# Copyright lowRISC contributors (OpenTitan project).
# Licensed under the Apache License, Version 2.0, see LICENSE for details.
# SPDX-License-Identifier: Apache-2.0
#
# This file was derived by lowRISC contributors (OpenTitan project) from the
# IHP Open PDK SRAM abstract RM_IHPSG13_1P_8192x32_c4.lef
# (https://github.com/IHP-GmbH/IHP-Open-PDK, ihp-sg13g2/libs.ref/sg13g2_sram/lef).
# It is a synthetic abstract, not an IHP release: the macro size and pins come
# from the Liberty view, the pin shapes, power straps and antenna values from
# the IHP abstract. IHP's original notice follows:
#
#   Copyright 2023 IHP PDK Authors
#
#   Licensed under the Apache License, Version 2.0 (the "License");
#   you may not use this file except in compliance with the License.
#   You may obtain a copy of the License at
#
#      https://www.apache.org/licenses/LICENSE-2.0
#
#   Unless required by applicable law or agreed to in writing, software
#   distributed under the License is distributed on an "AS IS" BASIS,
#   WITHOUT WARRANTIES OR CONDITIONS OF ANY KIND, either express or implied.
#   See the License for the specific language governing permissions and
#   limitations under the License.
#
#   Generated on Mon Apr  7 14:15:46 2025
#
# Generated by gen_synthetic_lef.py from the Liberty view. Do not edit.
# Synthetic abstract: no physical layout exists behind this macro.

VERSION 5.7 ;
BUSBITCHARS "[]" ;
DIVIDERCHAR "/" ;

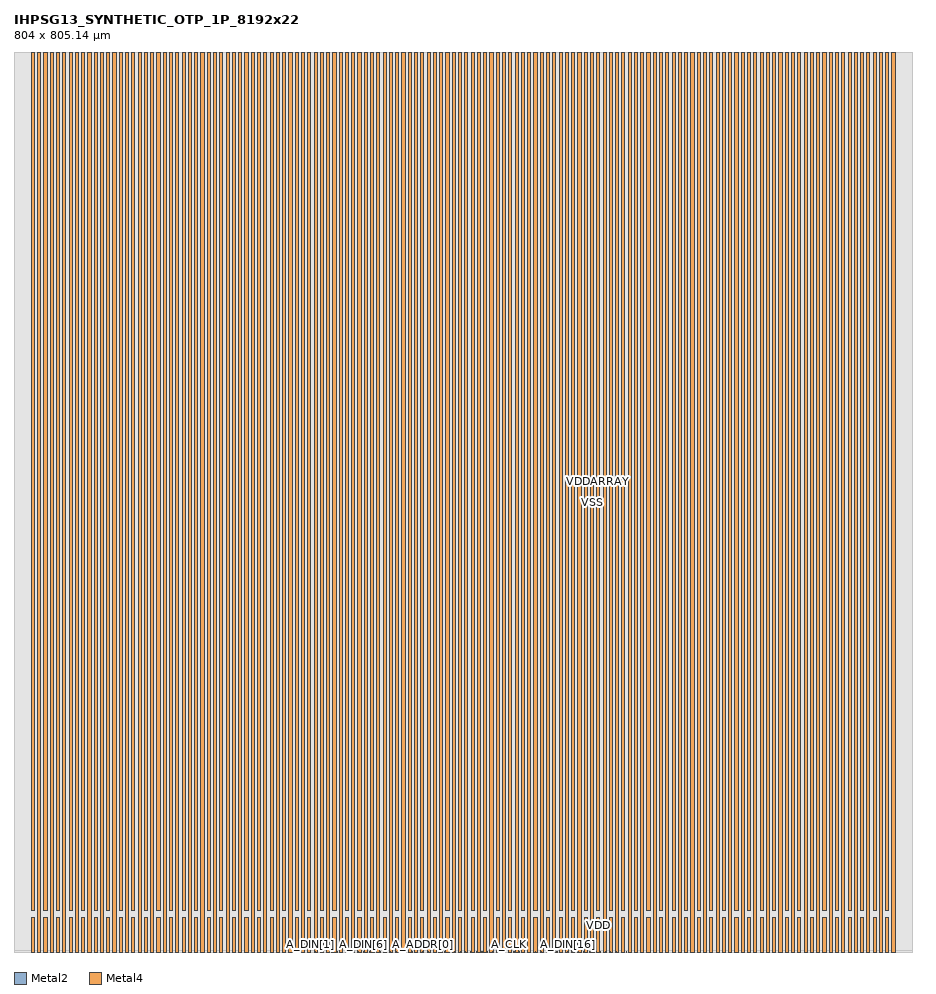
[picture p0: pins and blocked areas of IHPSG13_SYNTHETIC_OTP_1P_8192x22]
MACRO IHPSG13_SYNTHETIC_OTP_1P_8192x22
  CLASS BLOCK ;
  ORIGIN 0 0 ;
  FOREIGN IHPSG13_SYNTHETIC_OTP_1P_8192x22 0 0 ;
  SIZE 804 BY 805.14 ;
  SYMMETRY X Y R90 ;
  PIN A_DIN[0]
    DIRECTION INPUT ;
    USE SIGNAL ;
    ANTENNAMODEL OXIDE1 ;
      ANTENNAGATEAREA 0.20085 LAYER Metal2 ;
    PORT
      LAYER Metal2 ;
        RECT 255.23 0 255.49 0.26 ;
    END
  END A_DIN[0]
  PIN A_DOUT[0]
    DIRECTION OUTPUT ;
    USE SIGNAL ;
    ANTENNADIFFAREA 0.988 LAYER Metal2 ;
    PORT
      LAYER Metal2 ;
        RECT 260.03 0 260.29 0.26 ;
    END
  END A_DOUT[0]
  PIN A_DIN[1]
    DIRECTION INPUT ;
    USE SIGNAL ;
    ANTENNAMODEL OXIDE1 ;
      ANTENNAGATEAREA 0.20085 LAYER Metal2 ;
    PORT
      LAYER Metal2 ;
        RECT 264.83 0 265.09 0.26 ;
    END
  END A_DIN[1]
  PIN A_DOUT[1]
    DIRECTION OUTPUT ;
    USE SIGNAL ;
    ANTENNADIFFAREA 0.988 LAYER Metal2 ;
    PORT
      LAYER Metal2 ;
        RECT 269.63 0 269.89 0.26 ;
    END
  END A_DOUT[1]
  PIN A_DIN[2]
    DIRECTION INPUT ;
    USE SIGNAL ;
    ANTENNAMODEL OXIDE1 ;
      ANTENNAGATEAREA 0.20085 LAYER Metal2 ;
    PORT
      LAYER Metal2 ;
        RECT 274.43 0 274.69 0.26 ;
    END
  END A_DIN[2]
  PIN A_DOUT[2]
    DIRECTION OUTPUT ;
    USE SIGNAL ;
    ANTENNADIFFAREA 0.988 LAYER Metal2 ;
    PORT
      LAYER Metal2 ;
        RECT 279.23 0 279.49 0.26 ;
    END
  END A_DOUT[2]
  PIN A_DIN[3]
    DIRECTION INPUT ;
    USE SIGNAL ;
    ANTENNAMODEL OXIDE1 ;
      ANTENNAGATEAREA 0.20085 LAYER Metal2 ;
    PORT
      LAYER Metal2 ;
        RECT 284.03 0 284.29 0.26 ;
    END
  END A_DIN[3]
  PIN A_DOUT[3]
    DIRECTION OUTPUT ;
    USE SIGNAL ;
    ANTENNADIFFAREA 0.988 LAYER Metal2 ;
    PORT
      LAYER Metal2 ;
        RECT 288.83 0 289.09 0.26 ;
    END
  END A_DOUT[3]
  PIN A_DIN[4]
    DIRECTION INPUT ;
    USE SIGNAL ;
    ANTENNAMODEL OXIDE1 ;
      ANTENNAGATEAREA 0.20085 LAYER Metal2 ;
    PORT
      LAYER Metal2 ;
        RECT 293.63 0 293.89 0.26 ;
    END
  END A_DIN[4]
  PIN A_DOUT[4]
    DIRECTION OUTPUT ;
    USE SIGNAL ;
    ANTENNADIFFAREA 0.988 LAYER Metal2 ;
    PORT
      LAYER Metal2 ;
        RECT 298.43 0 298.69 0.26 ;
    END
  END A_DOUT[4]
  PIN A_DIN[5]
    DIRECTION INPUT ;
    USE SIGNAL ;
    ANTENNAMODEL OXIDE1 ;
      ANTENNAGATEAREA 0.20085 LAYER Metal2 ;
    PORT
      LAYER Metal2 ;
        RECT 303.23 0 303.49 0.26 ;
    END
  END A_DIN[5]
  PIN A_DOUT[5]
    DIRECTION OUTPUT ;
    USE SIGNAL ;
    ANTENNADIFFAREA 0.988 LAYER Metal2 ;
    PORT
      LAYER Metal2 ;
        RECT 308.03 0 308.29 0.26 ;
    END
  END A_DOUT[5]
  PIN A_DIN[6]
    DIRECTION INPUT ;
    USE SIGNAL ;
    ANTENNAMODEL OXIDE1 ;
      ANTENNAGATEAREA 0.20085 LAYER Metal2 ;
    PORT
      LAYER Metal2 ;
        RECT 312.83 0 313.09 0.26 ;
    END
  END A_DIN[6]
  PIN A_DOUT[6]
    DIRECTION OUTPUT ;
    USE SIGNAL ;
    ANTENNADIFFAREA 0.988 LAYER Metal2 ;
    PORT
      LAYER Metal2 ;
        RECT 317.63 0 317.89 0.26 ;
    END
  END A_DOUT[6]
  PIN A_DIN[7]
    DIRECTION INPUT ;
    USE SIGNAL ;
    ANTENNAMODEL OXIDE1 ;
      ANTENNAGATEAREA 0.20085 LAYER Metal2 ;
    PORT
      LAYER Metal2 ;
        RECT 322.43 0 322.69 0.26 ;
    END
  END A_DIN[7]
  PIN A_DOUT[7]
    DIRECTION OUTPUT ;
    USE SIGNAL ;
    ANTENNADIFFAREA 0.988 LAYER Metal2 ;
    PORT
      LAYER Metal2 ;
        RECT 327.23 0 327.49 0.26 ;
    END
  END A_DOUT[7]
  PIN A_DIN[8]
    DIRECTION INPUT ;
    USE SIGNAL ;
    ANTENNAMODEL OXIDE1 ;
      ANTENNAGATEAREA 0.20085 LAYER Metal2 ;
    PORT
      LAYER Metal2 ;
        RECT 332.03 0 332.29 0.26 ;
    END
  END A_DIN[8]
  PIN A_DOUT[8]
    DIRECTION OUTPUT ;
    USE SIGNAL ;
    ANTENNADIFFAREA 0.988 LAYER Metal2 ;
    PORT
      LAYER Metal2 ;
        RECT 336.83 0 337.09 0.26 ;
    END
  END A_DOUT[8]
  PIN A_DIN[9]
    DIRECTION INPUT ;
    USE SIGNAL ;
    ANTENNAMODEL OXIDE1 ;
      ANTENNAGATEAREA 0.20085 LAYER Metal2 ;
    PORT
      LAYER Metal2 ;
        RECT 341.63 0 341.89 0.26 ;
    END
  END A_DIN[9]
  PIN A_DOUT[9]
    DIRECTION OUTPUT ;
    USE SIGNAL ;
    ANTENNADIFFAREA 0.988 LAYER Metal2 ;
    PORT
      LAYER Metal2 ;
        RECT 346.43 0 346.69 0.26 ;
    END
  END A_DOUT[9]
  PIN A_DIN[10]
    DIRECTION INPUT ;
    USE SIGNAL ;
    ANTENNAMODEL OXIDE1 ;
      ANTENNAGATEAREA 0.20085 LAYER Metal2 ;
    PORT
      LAYER Metal2 ;
        RECT 351.23 0 351.49 0.26 ;
    END
  END A_DIN[10]
  PIN A_DOUT[10]
    DIRECTION OUTPUT ;
    USE SIGNAL ;
    ANTENNADIFFAREA 0.988 LAYER Metal2 ;
    PORT
      LAYER Metal2 ;
        RECT 356.03 0 356.29 0.26 ;
    END
  END A_DOUT[10]
  PIN A_DLY
    DIRECTION INPUT ;
    USE SIGNAL ;
    ANTENNAMODEL OXIDE1 ;
      ANTENNAGATEAREA 0.20085 LAYER Metal2 ;
    PORT
      LAYER Metal2 ;
        RECT 360.83 0 361.09 0.26 ;
    END
  END A_DLY
  PIN A_ADDR[0]
    DIRECTION INPUT ;
    USE SIGNAL ;
    ANTENNAMODEL OXIDE1 ;
      ANTENNAGATEAREA 0.20085 LAYER Metal2 ;
    PORT
      LAYER Metal2 ;
        RECT 365.63 0 365.89 0.26 ;
    END
  END A_ADDR[0]
  PIN A_ADDR[1]
    DIRECTION INPUT ;
    USE SIGNAL ;
    ANTENNAMODEL OXIDE1 ;
      ANTENNAGATEAREA 0.20085 LAYER Metal2 ;
    PORT
      LAYER Metal2 ;
        RECT 370.43 0 370.69 0.26 ;
    END
  END A_ADDR[1]
  PIN A_ADDR[2]
    DIRECTION INPUT ;
    USE SIGNAL ;
    ANTENNAMODEL OXIDE1 ;
      ANTENNAGATEAREA 0.20085 LAYER Metal2 ;
    PORT
      LAYER Metal2 ;
        RECT 375.23 0 375.49 0.26 ;
    END
  END A_ADDR[2]
  PIN A_ADDR[3]
    DIRECTION INPUT ;
    USE SIGNAL ;
    ANTENNAMODEL OXIDE1 ;
      ANTENNAGATEAREA 0.20085 LAYER Metal2 ;
    PORT
      LAYER Metal2 ;
        RECT 380.03 0 380.29 0.26 ;
    END
  END A_ADDR[3]
  PIN A_ADDR[4]
    DIRECTION INPUT ;
    USE SIGNAL ;
    ANTENNAMODEL OXIDE1 ;
      ANTENNAGATEAREA 0.20085 LAYER Metal2 ;
    PORT
      LAYER Metal2 ;
        RECT 384.83 0 385.09 0.26 ;
    END
  END A_ADDR[4]
  PIN A_ADDR[5]
    DIRECTION INPUT ;
    USE SIGNAL ;
    ANTENNAMODEL OXIDE1 ;
      ANTENNAGATEAREA 0.20085 LAYER Metal2 ;
    PORT
      LAYER Metal2 ;
        RECT 389.63 0 389.89 0.26 ;
    END
  END A_ADDR[5]
  PIN A_ADDR[6]
    DIRECTION INPUT ;
    USE SIGNAL ;
    ANTENNAMODEL OXIDE1 ;
      ANTENNAGATEAREA 0.20085 LAYER Metal2 ;
    PORT
      LAYER Metal2 ;
        RECT 394.43 0 394.69 0.26 ;
    END
  END A_ADDR[6]
  PIN A_ADDR[7]
    DIRECTION INPUT ;
    USE SIGNAL ;
    ANTENNAMODEL OXIDE1 ;
      ANTENNAGATEAREA 0.20085 LAYER Metal2 ;
    PORT
      LAYER Metal2 ;
        RECT 399.23 0 399.49 0.26 ;
    END
  END A_ADDR[7]
  PIN A_ADDR[8]
    DIRECTION INPUT ;
    USE SIGNAL ;
    ANTENNAMODEL OXIDE1 ;
      ANTENNAGATEAREA 0.20085 LAYER Metal2 ;
    PORT
      LAYER Metal2 ;
        RECT 404.03 0 404.29 0.26 ;
    END
  END A_ADDR[8]
  PIN A_ADDR[9]
    DIRECTION INPUT ;
    USE SIGNAL ;
    ANTENNAMODEL OXIDE1 ;
      ANTENNAGATEAREA 0.20085 LAYER Metal2 ;
    PORT
      LAYER Metal2 ;
        RECT 408.83 0 409.09 0.26 ;
    END
  END A_ADDR[9]
  PIN A_ADDR[10]
    DIRECTION INPUT ;
    USE SIGNAL ;
    ANTENNAMODEL OXIDE1 ;
      ANTENNAGATEAREA 0.20085 LAYER Metal2 ;
    PORT
      LAYER Metal2 ;
        RECT 413.63 0 413.89 0.26 ;
    END
  END A_ADDR[10]
  PIN A_ADDR[11]
    DIRECTION INPUT ;
    USE SIGNAL ;
    ANTENNAMODEL OXIDE1 ;
      ANTENNAGATEAREA 0.20085 LAYER Metal2 ;
    PORT
      LAYER Metal2 ;
        RECT 418.43 0 418.69 0.26 ;
    END
  END A_ADDR[11]
  PIN A_ADDR[12]
    DIRECTION INPUT ;
    USE SIGNAL ;
    ANTENNAMODEL OXIDE1 ;
      ANTENNAGATEAREA 0.20085 LAYER Metal2 ;
    PORT
      LAYER Metal2 ;
        RECT 423.23 0 423.49 0.26 ;
    END
  END A_ADDR[12]
  PIN A_WEN
    DIRECTION INPUT ;
    USE SIGNAL ;
    ANTENNAMODEL OXIDE1 ;
      ANTENNAGATEAREA 0.20085 LAYER Metal2 ;
    PORT
      LAYER Metal2 ;
        RECT 428.03 0 428.29 0.26 ;
    END
  END A_WEN
  PIN A_REN
    DIRECTION INPUT ;
    USE SIGNAL ;
    ANTENNAMODEL OXIDE1 ;
      ANTENNAGATEAREA 0.20085 LAYER Metal2 ;
    PORT
      LAYER Metal2 ;
        RECT 432.83 0 433.09 0.26 ;
    END
  END A_REN
  PIN A_MEN
    DIRECTION INPUT ;
    USE SIGNAL ;
    ANTENNAMODEL OXIDE1 ;
      ANTENNAGATEAREA 0.20085 LAYER Metal2 ;
    PORT
      LAYER Metal2 ;
        RECT 437.63 0 437.89 0.26 ;
    END
  END A_MEN
  PIN A_CLK
    DIRECTION INPUT ;
    USE SIGNAL ;
    ANTENNAMODEL OXIDE1 ;
      ANTENNAGATEAREA 0.20085 LAYER Metal2 ;
    PORT
      LAYER Metal2 ;
        RECT 442.43 0 442.69 0.26 ;
    END
  END A_CLK
  PIN A_DIN[11]
    DIRECTION INPUT ;
    USE SIGNAL ;
    ANTENNAMODEL OXIDE1 ;
      ANTENNAGATEAREA 0.20085 LAYER Metal2 ;
    PORT
      LAYER Metal2 ;
        RECT 447.23 0 447.49 0.26 ;
    END
  END A_DIN[11]
  PIN A_DOUT[11]
    DIRECTION OUTPUT ;
    USE SIGNAL ;
    ANTENNADIFFAREA 0.988 LAYER Metal2 ;
    PORT
      LAYER Metal2 ;
        RECT 452.03 0 452.29 0.26 ;
    END
  END A_DOUT[11]
  PIN A_DIN[12]
    DIRECTION INPUT ;
    USE SIGNAL ;
    ANTENNAMODEL OXIDE1 ;
      ANTENNAGATEAREA 0.20085 LAYER Metal2 ;
    PORT
      LAYER Metal2 ;
        RECT 456.83 0 457.09 0.26 ;
    END
  END A_DIN[12]
  PIN A_DOUT[12]
    DIRECTION OUTPUT ;
    USE SIGNAL ;
    ANTENNADIFFAREA 0.988 LAYER Metal2 ;
    PORT
      LAYER Metal2 ;
        RECT 461.63 0 461.89 0.26 ;
    END
  END A_DOUT[12]
  PIN A_DIN[13]
    DIRECTION INPUT ;
    USE SIGNAL ;
    ANTENNAMODEL OXIDE1 ;
      ANTENNAGATEAREA 0.20085 LAYER Metal2 ;
    PORT
      LAYER Metal2 ;
        RECT 466.43 0 466.69 0.26 ;
    END
  END A_DIN[13]
  PIN A_DOUT[13]
    DIRECTION OUTPUT ;
    USE SIGNAL ;
    ANTENNADIFFAREA 0.988 LAYER Metal2 ;
    PORT
      LAYER Metal2 ;
        RECT 471.23 0 471.49 0.26 ;
    END
  END A_DOUT[13]
  PIN A_DIN[14]
    DIRECTION INPUT ;
    USE SIGNAL ;
    ANTENNAMODEL OXIDE1 ;
      ANTENNAGATEAREA 0.20085 LAYER Metal2 ;
    PORT
      LAYER Metal2 ;
        RECT 476.03 0 476.29 0.26 ;
    END
  END A_DIN[14]
  PIN A_DOUT[14]
    DIRECTION OUTPUT ;
    USE SIGNAL ;
    ANTENNADIFFAREA 0.988 LAYER Metal2 ;
    PORT
      LAYER Metal2 ;
        RECT 480.83 0 481.09 0.26 ;
    END
  END A_DOUT[14]
  PIN A_DIN[15]
    DIRECTION INPUT ;
    USE SIGNAL ;
    ANTENNAMODEL OXIDE1 ;
      ANTENNAGATEAREA 0.20085 LAYER Metal2 ;
    PORT
      LAYER Metal2 ;
        RECT 485.63 0 485.89 0.26 ;
    END
  END A_DIN[15]
  PIN A_DOUT[15]
    DIRECTION OUTPUT ;
    USE SIGNAL ;
    ANTENNADIFFAREA 0.988 LAYER Metal2 ;
    PORT
      LAYER Metal2 ;
        RECT 490.43 0 490.69 0.26 ;
    END
  END A_DOUT[15]
  PIN A_DIN[16]
    DIRECTION INPUT ;
    USE SIGNAL ;
    ANTENNAMODEL OXIDE1 ;
      ANTENNAGATEAREA 0.20085 LAYER Metal2 ;
    PORT
      LAYER Metal2 ;
        RECT 495.23 0 495.49 0.26 ;
    END
  END A_DIN[16]
  PIN A_DOUT[16]
    DIRECTION OUTPUT ;
    USE SIGNAL ;
    ANTENNADIFFAREA 0.988 LAYER Metal2 ;
    PORT
      LAYER Metal2 ;
        RECT 500.03 0 500.29 0.26 ;
    END
  END A_DOUT[16]
  PIN A_DIN[17]
    DIRECTION INPUT ;
    USE SIGNAL ;
    ANTENNAMODEL OXIDE1 ;
      ANTENNAGATEAREA 0.20085 LAYER Metal2 ;
    PORT
      LAYER Metal2 ;
        RECT 504.83 0 505.09 0.26 ;
    END
  END A_DIN[17]
  PIN A_DOUT[17]
    DIRECTION OUTPUT ;
    USE SIGNAL ;
    ANTENNADIFFAREA 0.988 LAYER Metal2 ;
    PORT
      LAYER Metal2 ;
        RECT 509.63 0 509.89 0.26 ;
    END
  END A_DOUT[17]
  PIN A_DIN[18]
    DIRECTION INPUT ;
    USE SIGNAL ;
    ANTENNAMODEL OXIDE1 ;
      ANTENNAGATEAREA 0.20085 LAYER Metal2 ;
    PORT
      LAYER Metal2 ;
        RECT 514.43 0 514.69 0.26 ;
    END
  END A_DIN[18]
  PIN A_DOUT[18]
    DIRECTION OUTPUT ;
    USE SIGNAL ;
    ANTENNADIFFAREA 0.988 LAYER Metal2 ;
    PORT
      LAYER Metal2 ;
        RECT 519.23 0 519.49 0.26 ;
    END
  END A_DOUT[18]
  PIN A_DIN[19]
    DIRECTION INPUT ;
    USE SIGNAL ;
    ANTENNAMODEL OXIDE1 ;
      ANTENNAGATEAREA 0.20085 LAYER Metal2 ;
    PORT
      LAYER Metal2 ;
        RECT 524.03 0 524.29 0.26 ;
    END
  END A_DIN[19]
  PIN A_DOUT[19]
    DIRECTION OUTPUT ;
    USE SIGNAL ;
    ANTENNADIFFAREA 0.988 LAYER Metal2 ;
    PORT
      LAYER Metal2 ;
        RECT 528.83 0 529.09 0.26 ;
    END
  END A_DOUT[19]
  PIN A_DIN[20]
    DIRECTION INPUT ;
    USE SIGNAL ;
    ANTENNAMODEL OXIDE1 ;
      ANTENNAGATEAREA 0.20085 LAYER Metal2 ;
    PORT
      LAYER Metal2 ;
        RECT 533.63 0 533.89 0.26 ;
    END
  END A_DIN[20]
  PIN A_DOUT[20]
    DIRECTION OUTPUT ;
    USE SIGNAL ;
    ANTENNADIFFAREA 0.988 LAYER Metal2 ;
    PORT
      LAYER Metal2 ;
        RECT 538.43 0 538.69 0.26 ;
    END
  END A_DOUT[20]
  PIN A_DIN[21]
    DIRECTION INPUT ;
    USE SIGNAL ;
    ANTENNAMODEL OXIDE1 ;
      ANTENNAGATEAREA 0.20085 LAYER Metal2 ;
    PORT
      LAYER Metal2 ;
        RECT 543.23 0 543.49 0.26 ;
    END
  END A_DIN[21]
  PIN A_DOUT[21]
    DIRECTION OUTPUT ;
    USE SIGNAL ;
    ANTENNADIFFAREA 0.988 LAYER Metal2 ;
    PORT
      LAYER Metal2 ;
        RECT 548.03 0 548.29 0.26 ;
    END
  END A_DOUT[21]
  PIN VDD
    DIRECTION INOUT ;
    USE POWER ;
    PORT
      LAYER Metal4 ;
        RECT 15.5 0 18.31 30.425 ;
    END
    PORT
      LAYER Metal4 ;
        RECT 26.74 0 29.55 30.425 ;
    END
    PORT
      LAYER Metal4 ;
        RECT 37.98 0 40.79 30.425 ;
    END
    PORT
      LAYER Metal4 ;
        RECT 49.22 0 52.03 30.425 ;
    END
    PORT
      LAYER Metal4 ;
        RECT 60.46 0 63.27 30.425 ;
    END
    PORT
      LAYER Metal4 ;
        RECT 71.7 0 74.51 30.425 ;
    END
    PORT
      LAYER Metal4 ;
        RECT 82.94 0 85.75 30.425 ;
    END
    PORT
      LAYER Metal4 ;
        RECT 94.18 0 96.99 30.425 ;
    END
    PORT
      LAYER Metal4 ;
        RECT 105.42 0 108.23 30.425 ;
    END
    PORT
      LAYER Metal4 ;
        RECT 116.66 0 119.47 30.425 ;
    END
    PORT
      LAYER Metal4 ;
        RECT 127.9 0 130.71 30.425 ;
    END
    PORT
      LAYER Metal4 ;
        RECT 139.14 0 141.95 30.425 ;
    END
    PORT
      LAYER Metal4 ;
        RECT 150.38 0 153.19 30.425 ;
    END
    PORT
      LAYER Metal4 ;
        RECT 161.62 0 164.43 30.425 ;
    END
    PORT
      LAYER Metal4 ;
        RECT 172.86 0 175.67 30.425 ;
    END
    PORT
      LAYER Metal4 ;
        RECT 184.1 0 186.91 30.425 ;
    END
    PORT
      LAYER Metal4 ;
        RECT 195.34 0 198.15 30.425 ;
    END
    PORT
      LAYER Metal4 ;
        RECT 206.58 0 209.39 30.425 ;
    END
    PORT
      LAYER Metal4 ;
        RECT 217.82 0 220.63 30.425 ;
    END
    PORT
      LAYER Metal4 ;
        RECT 229.06 0 231.87 30.425 ;
    END
    PORT
      LAYER Metal4 ;
        RECT 240.3 0 243.11 30.425 ;
    END
    PORT
      LAYER Metal4 ;
        RECT 251.54 0 254.35 30.425 ;
    END
    PORT
      LAYER Metal4 ;
        RECT 262.78 0 265.59 30.425 ;
    END
    PORT
      LAYER Metal4 ;
        RECT 274.02 0 276.83 30.425 ;
    END
    PORT
      LAYER Metal4 ;
        RECT 285.26 0 288.07 30.425 ;
    END
    PORT
      LAYER Metal4 ;
        RECT 296.5 0 299.31 30.425 ;
    END
    PORT
      LAYER Metal4 ;
        RECT 307.74 0 310.55 30.425 ;
    END
    PORT
      LAYER Metal4 ;
        RECT 318.98 0 321.79 30.425 ;
    END
    PORT
      LAYER Metal4 ;
        RECT 330.22 0 333.03 30.425 ;
    END
    PORT
      LAYER Metal4 ;
        RECT 341.46 0 344.27 30.425 ;
    END
    PORT
      LAYER Metal4 ;
        RECT 352.7 0 355.51 30.425 ;
    END
    PORT
      LAYER Metal4 ;
        RECT 363.94 0 366.75 30.425 ;
    END
    PORT
      LAYER Metal4 ;
        RECT 375.18 0 377.99 30.425 ;
    END
    PORT
      LAYER Metal4 ;
        RECT 386.42 0 389.23 30.425 ;
    END
    PORT
      LAYER Metal4 ;
        RECT 397.66 0 400.47 30.425 ;
    END
    PORT
      LAYER Metal4 ;
        RECT 408.9 0 411.71 30.425 ;
    END
    PORT
      LAYER Metal4 ;
        RECT 420.14 0 422.95 30.425 ;
    END
    PORT
      LAYER Metal4 ;
        RECT 431.38 0 434.19 30.425 ;
    END
    PORT
      LAYER Metal4 ;
        RECT 442.62 0 445.43 30.425 ;
    END
    PORT
      LAYER Metal4 ;
        RECT 453.86 0 456.67 30.425 ;
    END
    PORT
      LAYER Metal4 ;
        RECT 465.1 0 467.91 30.425 ;
    END
    PORT
      LAYER Metal4 ;
        RECT 476.34 0 479.15 30.425 ;
    END
    PORT
      LAYER Metal4 ;
        RECT 487.58 0 490.39 30.425 ;
    END
    PORT
      LAYER Metal4 ;
        RECT 498.82 0 501.63 30.425 ;
    END
    PORT
      LAYER Metal4 ;
        RECT 510.06 0 512.87 30.425 ;
    END
    PORT
      LAYER Metal4 ;
        RECT 521.3 0 524.11 30.425 ;
    END
    PORT
      LAYER Metal4 ;
        RECT 532.54 0 535.35 30.425 ;
    END
    PORT
      LAYER Metal4 ;
        RECT 543.78 0 546.59 30.425 ;
    END
    PORT
      LAYER Metal4 ;
        RECT 555.02 0 557.83 30.425 ;
    END
    PORT
      LAYER Metal4 ;
        RECT 566.26 0 569.07 30.425 ;
    END
    PORT
      LAYER Metal4 ;
        RECT 577.5 0 580.31 30.425 ;
    END
    PORT
      LAYER Metal4 ;
        RECT 588.74 0 591.55 30.425 ;
    END
    PORT
      LAYER Metal4 ;
        RECT 599.98 0 602.79 30.425 ;
    END
    PORT
      LAYER Metal4 ;
        RECT 611.22 0 614.03 30.425 ;
    END
    PORT
      LAYER Metal4 ;
        RECT 622.46 0 625.27 30.425 ;
    END
    PORT
      LAYER Metal4 ;
        RECT 633.7 0 636.51 30.425 ;
    END
    PORT
      LAYER Metal4 ;
        RECT 644.94 0 647.75 30.425 ;
    END
    PORT
      LAYER Metal4 ;
        RECT 656.18 0 658.99 30.425 ;
    END
    PORT
      LAYER Metal4 ;
        RECT 667.42 0 670.23 30.425 ;
    END
    PORT
      LAYER Metal4 ;
        RECT 678.66 0 681.47 30.425 ;
    END
    PORT
      LAYER Metal4 ;
        RECT 689.9 0 692.71 30.425 ;
    END
    PORT
      LAYER Metal4 ;
        RECT 701.14 0 703.95 30.425 ;
    END
    PORT
      LAYER Metal4 ;
        RECT 712.38 0 715.19 30.425 ;
    END
    PORT
      LAYER Metal4 ;
        RECT 723.62 0 726.43 30.425 ;
    END
    PORT
      LAYER Metal4 ;
        RECT 734.86 0 737.67 30.425 ;
    END
    PORT
      LAYER Metal4 ;
        RECT 746.1 0 748.91 30.425 ;
    END
    PORT
      LAYER Metal4 ;
        RECT 757.34 0 760.15 30.425 ;
    END
    PORT
      LAYER Metal4 ;
        RECT 768.58 0 771.39 30.425 ;
    END
    PORT
      LAYER Metal4 ;
        RECT 779.82 0 782.63 30.425 ;
    END
  END VDD
  PIN VDDARRAY
    DIRECTION INOUT ;
    USE POWER ;
    PORT
      LAYER Metal4 ;
        RECT 15.5 37.065 18.31 805.14 ;
    END
    PORT
      LAYER Metal4 ;
        RECT 26.74 37.065 29.55 805.14 ;
    END
    PORT
      LAYER Metal4 ;
        RECT 37.98 37.065 40.79 805.14 ;
    END
    PORT
      LAYER Metal4 ;
        RECT 49.22 37.065 52.03 805.14 ;
    END
    PORT
      LAYER Metal4 ;
        RECT 60.46 37.065 63.27 805.14 ;
    END
    PORT
      LAYER Metal4 ;
        RECT 71.7 37.065 74.51 805.14 ;
    END
    PORT
      LAYER Metal4 ;
        RECT 82.94 37.065 85.75 805.14 ;
    END
    PORT
      LAYER Metal4 ;
        RECT 94.18 37.065 96.99 805.14 ;
    END
    PORT
      LAYER Metal4 ;
        RECT 105.42 37.065 108.23 805.14 ;
    END
    PORT
      LAYER Metal4 ;
        RECT 116.66 37.065 119.47 805.14 ;
    END
    PORT
      LAYER Metal4 ;
        RECT 127.9 37.065 130.71 805.14 ;
    END
    PORT
      LAYER Metal4 ;
        RECT 139.14 37.065 141.95 805.14 ;
    END
    PORT
      LAYER Metal4 ;
        RECT 150.38 37.065 153.19 805.14 ;
    END
    PORT
      LAYER Metal4 ;
        RECT 161.62 37.065 164.43 805.14 ;
    END
    PORT
      LAYER Metal4 ;
        RECT 172.86 37.065 175.67 805.14 ;
    END
    PORT
      LAYER Metal4 ;
        RECT 184.1 37.065 186.91 805.14 ;
    END
    PORT
      LAYER Metal4 ;
        RECT 195.34 37.065 198.15 805.14 ;
    END
    PORT
      LAYER Metal4 ;
        RECT 206.58 37.065 209.39 805.14 ;
    END
    PORT
      LAYER Metal4 ;
        RECT 217.82 37.065 220.63 805.14 ;
    END
    PORT
      LAYER Metal4 ;
        RECT 229.06 37.065 231.87 805.14 ;
    END
    PORT
      LAYER Metal4 ;
        RECT 240.3 37.065 243.11 805.14 ;
    END
    PORT
      LAYER Metal4 ;
        RECT 251.54 37.065 254.35 805.14 ;
    END
    PORT
      LAYER Metal4 ;
        RECT 262.78 37.065 265.59 805.14 ;
    END
    PORT
      LAYER Metal4 ;
        RECT 274.02 37.065 276.83 805.14 ;
    END
    PORT
      LAYER Metal4 ;
        RECT 285.26 37.065 288.07 805.14 ;
    END
    PORT
      LAYER Metal4 ;
        RECT 296.5 37.065 299.31 805.14 ;
    END
    PORT
      LAYER Metal4 ;
        RECT 307.74 37.065 310.55 805.14 ;
    END
    PORT
      LAYER Metal4 ;
        RECT 318.98 37.065 321.79 805.14 ;
    END
    PORT
      LAYER Metal4 ;
        RECT 330.22 37.065 333.03 805.14 ;
    END
    PORT
      LAYER Metal4 ;
        RECT 341.46 37.065 344.27 805.14 ;
    END
    PORT
      LAYER Metal4 ;
        RECT 352.7 37.065 355.51 805.14 ;
    END
    PORT
      LAYER Metal4 ;
        RECT 363.94 37.065 366.75 805.14 ;
    END
    PORT
      LAYER Metal4 ;
        RECT 375.18 37.065 377.99 805.14 ;
    END
    PORT
      LAYER Metal4 ;
        RECT 386.42 37.065 389.23 805.14 ;
    END
    PORT
      LAYER Metal4 ;
        RECT 397.66 37.065 400.47 805.14 ;
    END
    PORT
      LAYER Metal4 ;
        RECT 408.9 37.065 411.71 805.14 ;
    END
    PORT
      LAYER Metal4 ;
        RECT 420.14 37.065 422.95 805.14 ;
    END
    PORT
      LAYER Metal4 ;
        RECT 431.38 37.065 434.19 805.14 ;
    END
    PORT
      LAYER Metal4 ;
        RECT 442.62 37.065 445.43 805.14 ;
    END
    PORT
      LAYER Metal4 ;
        RECT 453.86 37.065 456.67 805.14 ;
    END
    PORT
      LAYER Metal4 ;
        RECT 465.1 37.065 467.91 805.14 ;
    END
    PORT
      LAYER Metal4 ;
        RECT 476.34 37.065 479.15 805.14 ;
    END
    PORT
      LAYER Metal4 ;
        RECT 487.58 37.065 490.39 805.14 ;
    END
    PORT
      LAYER Metal4 ;
        RECT 498.82 37.065 501.63 805.14 ;
    END
    PORT
      LAYER Metal4 ;
        RECT 510.06 37.065 512.87 805.14 ;
    END
    PORT
      LAYER Metal4 ;
        RECT 521.3 37.065 524.11 805.14 ;
    END
    PORT
      LAYER Metal4 ;
        RECT 532.54 37.065 535.35 805.14 ;
    END
    PORT
      LAYER Metal4 ;
        RECT 543.78 37.065 546.59 805.14 ;
    END
    PORT
      LAYER Metal4 ;
        RECT 555.02 37.065 557.83 805.14 ;
    END
    PORT
      LAYER Metal4 ;
        RECT 566.26 37.065 569.07 805.14 ;
    END
    PORT
      LAYER Metal4 ;
        RECT 577.5 37.065 580.31 805.14 ;
    END
    PORT
      LAYER Metal4 ;
        RECT 588.74 37.065 591.55 805.14 ;
    END
    PORT
      LAYER Metal4 ;
        RECT 599.98 37.065 602.79 805.14 ;
    END
    PORT
      LAYER Metal4 ;
        RECT 611.22 37.065 614.03 805.14 ;
    END
    PORT
      LAYER Metal4 ;
        RECT 622.46 37.065 625.27 805.14 ;
    END
    PORT
      LAYER Metal4 ;
        RECT 633.7 37.065 636.51 805.14 ;
    END
    PORT
      LAYER Metal4 ;
        RECT 644.94 37.065 647.75 805.14 ;
    END
    PORT
      LAYER Metal4 ;
        RECT 656.18 37.065 658.99 805.14 ;
    END
    PORT
      LAYER Metal4 ;
        RECT 667.42 37.065 670.23 805.14 ;
    END
    PORT
      LAYER Metal4 ;
        RECT 678.66 37.065 681.47 805.14 ;
    END
    PORT
      LAYER Metal4 ;
        RECT 689.9 37.065 692.71 805.14 ;
    END
    PORT
      LAYER Metal4 ;
        RECT 701.14 37.065 703.95 805.14 ;
    END
    PORT
      LAYER Metal4 ;
        RECT 712.38 37.065 715.19 805.14 ;
    END
    PORT
      LAYER Metal4 ;
        RECT 723.62 37.065 726.43 805.14 ;
    END
    PORT
      LAYER Metal4 ;
        RECT 734.86 37.065 737.67 805.14 ;
    END
    PORT
      LAYER Metal4 ;
        RECT 746.1 37.065 748.91 805.14 ;
    END
    PORT
      LAYER Metal4 ;
        RECT 757.34 37.065 760.15 805.14 ;
    END
    PORT
      LAYER Metal4 ;
        RECT 768.58 37.065 771.39 805.14 ;
    END
    PORT
      LAYER Metal4 ;
        RECT 779.82 37.065 782.63 805.14 ;
    END
  END VDDARRAY
  PIN VSS
    DIRECTION INOUT ;
    USE GROUND ;
    PORT
      LAYER Metal4 ;
        RECT 21.12 0 23.93 805.14 ;
    END
    PORT
      LAYER Metal4 ;
        RECT 32.36 0 35.17 805.14 ;
    END
    PORT
      LAYER Metal4 ;
        RECT 43.6 0 46.41 805.14 ;
    END
    PORT
      LAYER Metal4 ;
        RECT 54.84 0 57.65 805.14 ;
    END
    PORT
      LAYER Metal4 ;
        RECT 66.08 0 68.89 805.14 ;
    END
    PORT
      LAYER Metal4 ;
        RECT 77.32 0 80.13 805.14 ;
    END
    PORT
      LAYER Metal4 ;
        RECT 88.56 0 91.37 805.14 ;
    END
    PORT
      LAYER Metal4 ;
        RECT 99.8 0 102.61 805.14 ;
    END
    PORT
      LAYER Metal4 ;
        RECT 111.04 0 113.85 805.14 ;
    END
    PORT
      LAYER Metal4 ;
        RECT 122.28 0 125.09 805.14 ;
    END
    PORT
      LAYER Metal4 ;
        RECT 133.52 0 136.33 805.14 ;
    END
    PORT
      LAYER Metal4 ;
        RECT 144.76 0 147.57 805.14 ;
    END
    PORT
      LAYER Metal4 ;
        RECT 156 0 158.81 805.14 ;
    END
    PORT
      LAYER Metal4 ;
        RECT 167.24 0 170.05 805.14 ;
    END
    PORT
      LAYER Metal4 ;
        RECT 178.48 0 181.29 805.14 ;
    END
    PORT
      LAYER Metal4 ;
        RECT 189.72 0 192.53 805.14 ;
    END
    PORT
      LAYER Metal4 ;
        RECT 200.96 0 203.77 805.14 ;
    END
    PORT
      LAYER Metal4 ;
        RECT 212.2 0 215.01 805.14 ;
    END
    PORT
      LAYER Metal4 ;
        RECT 223.44 0 226.25 805.14 ;
    END
    PORT
      LAYER Metal4 ;
        RECT 234.68 0 237.49 805.14 ;
    END
    PORT
      LAYER Metal4 ;
        RECT 245.92 0 248.73 805.14 ;
    END
    PORT
      LAYER Metal4 ;
        RECT 257.16 0 259.97 805.14 ;
    END
    PORT
      LAYER Metal4 ;
        RECT 268.4 0 271.21 805.14 ;
    END
    PORT
      LAYER Metal4 ;
        RECT 279.64 0 282.45 805.14 ;
    END
    PORT
      LAYER Metal4 ;
        RECT 290.88 0 293.69 805.14 ;
    END
    PORT
      LAYER Metal4 ;
        RECT 302.12 0 304.93 805.14 ;
    END
    PORT
      LAYER Metal4 ;
        RECT 313.36 0 316.17 805.14 ;
    END
    PORT
      LAYER Metal4 ;
        RECT 324.6 0 327.41 805.14 ;
    END
    PORT
      LAYER Metal4 ;
        RECT 335.84 0 338.65 805.14 ;
    END
    PORT
      LAYER Metal4 ;
        RECT 347.08 0 349.89 805.14 ;
    END
    PORT
      LAYER Metal4 ;
        RECT 358.32 0 361.13 805.14 ;
    END
    PORT
      LAYER Metal4 ;
        RECT 369.56 0 372.37 805.14 ;
    END
    PORT
      LAYER Metal4 ;
        RECT 380.8 0 383.61 805.14 ;
    END
    PORT
      LAYER Metal4 ;
        RECT 392.04 0 394.85 805.14 ;
    END
    PORT
      LAYER Metal4 ;
        RECT 403.28 0 406.09 805.14 ;
    END
    PORT
      LAYER Metal4 ;
        RECT 414.52 0 417.33 805.14 ;
    END
    PORT
      LAYER Metal4 ;
        RECT 425.76 0 428.57 805.14 ;
    END
    PORT
      LAYER Metal4 ;
        RECT 437 0 439.81 805.14 ;
    END
    PORT
      LAYER Metal4 ;
        RECT 448.24 0 451.05 805.14 ;
    END
    PORT
      LAYER Metal4 ;
        RECT 459.48 0 462.29 805.14 ;
    END
    PORT
      LAYER Metal4 ;
        RECT 470.72 0 473.53 805.14 ;
    END
    PORT
      LAYER Metal4 ;
        RECT 481.96 0 484.77 805.14 ;
    END
    PORT
      LAYER Metal4 ;
        RECT 493.2 0 496.01 805.14 ;
    END
    PORT
      LAYER Metal4 ;
        RECT 504.44 0 507.25 805.14 ;
    END
    PORT
      LAYER Metal4 ;
        RECT 515.68 0 518.49 805.14 ;
    END
    PORT
      LAYER Metal4 ;
        RECT 526.92 0 529.73 805.14 ;
    END
    PORT
      LAYER Metal4 ;
        RECT 538.16 0 540.97 805.14 ;
    END
    PORT
      LAYER Metal4 ;
        RECT 549.4 0 552.21 805.14 ;
    END
    PORT
      LAYER Metal4 ;
        RECT 560.64 0 563.45 805.14 ;
    END
    PORT
      LAYER Metal4 ;
        RECT 571.88 0 574.69 805.14 ;
    END
    PORT
      LAYER Metal4 ;
        RECT 583.12 0 585.93 805.14 ;
    END
    PORT
      LAYER Metal4 ;
        RECT 594.36 0 597.17 805.14 ;
    END
    PORT
      LAYER Metal4 ;
        RECT 605.6 0 608.41 805.14 ;
    END
    PORT
      LAYER Metal4 ;
        RECT 616.84 0 619.65 805.14 ;
    END
    PORT
      LAYER Metal4 ;
        RECT 628.08 0 630.89 805.14 ;
    END
    PORT
      LAYER Metal4 ;
        RECT 639.32 0 642.13 805.14 ;
    END
    PORT
      LAYER Metal4 ;
        RECT 650.56 0 653.37 805.14 ;
    END
    PORT
      LAYER Metal4 ;
        RECT 661.8 0 664.61 805.14 ;
    END
    PORT
      LAYER Metal4 ;
        RECT 673.04 0 675.85 805.14 ;
    END
    PORT
      LAYER Metal4 ;
        RECT 684.28 0 687.09 805.14 ;
    END
    PORT
      LAYER Metal4 ;
        RECT 695.52 0 698.33 805.14 ;
    END
    PORT
      LAYER Metal4 ;
        RECT 706.76 0 709.57 805.14 ;
    END
    PORT
      LAYER Metal4 ;
        RECT 718 0 720.81 805.14 ;
    END
    PORT
      LAYER Metal4 ;
        RECT 729.24 0 732.05 805.14 ;
    END
    PORT
      LAYER Metal4 ;
        RECT 740.48 0 743.29 805.14 ;
    END
    PORT
      LAYER Metal4 ;
        RECT 751.72 0 754.53 805.14 ;
    END
    PORT
      LAYER Metal4 ;
        RECT 762.96 0 765.77 805.14 ;
    END
    PORT
      LAYER Metal4 ;
        RECT 774.2 0 777.01 805.14 ;
    END
    PORT
      LAYER Metal4 ;
        RECT 785.44 0 788.25 805.14 ;
    END
  END VSS
  OBS
    LAYER Metal1 ;
      RECT 0 0 804 805.14 ;
    LAYER Metal2 ;
      RECT 0 1 804 805.14 ;
    LAYER Metal3 ;
      RECT 0 1 804 805.14 ;
  END
END IHPSG13_SYNTHETIC_OTP_1P_8192x22

END LIBRARY
